One B-rep face of a CAD part: STEP entity #197.
In plain terms, the planar face has unit normal (1, 0, 0).
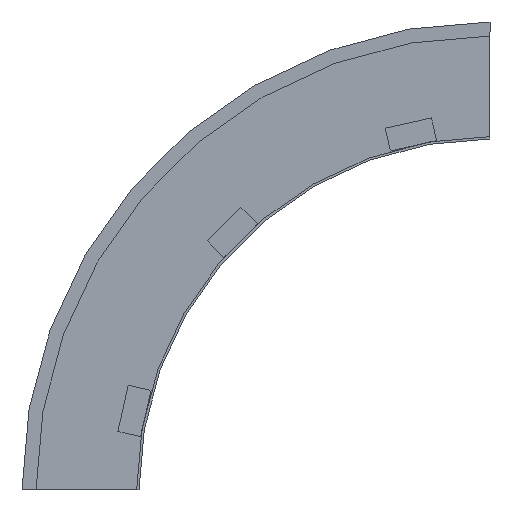
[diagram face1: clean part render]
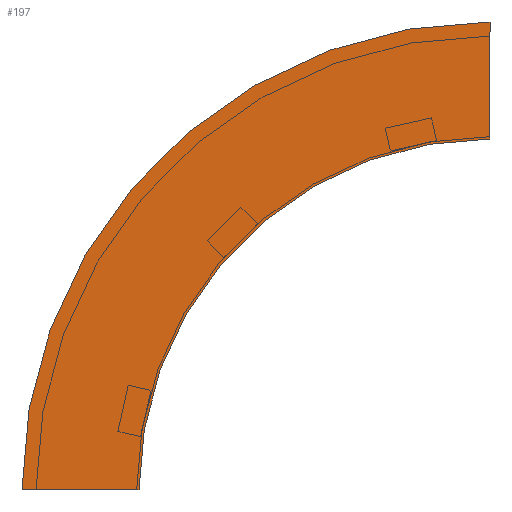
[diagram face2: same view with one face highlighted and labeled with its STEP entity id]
Its self-contained STEP definition (entity closure, numbers rounded to 3 decimals):
#60 = CIRCLE ( 'NONE', #221, 300. ) ;
#65 = DIRECTION ( 'NONE',  ( 0., 1., 0. ) ) ;
#71 = VECTOR ( 'NONE', #213, 1000. ) ;
#105 = CARTESIAN_POINT ( 'NONE',  ( 0., 0., 0. ) ) ;
#115 = ORIENTED_EDGE ( 'NONE', *, *, #181, .T. ) ;
#139 = EDGE_CURVE ( 'NONE', #254, #363, #551, .T. ) ;
#148 = CARTESIAN_POINT ( 'NONE',  ( 0., -300., 0. ) ) ;
#160 = CARTESIAN_POINT ( 'NONE',  ( 0., -300., 400. ) ) ;
#172 = EDGE_LOOP ( 'NONE', ( #115, #370, #451, #264 ) ) ;
#181 = EDGE_CURVE ( 'NONE', #363, #540, #483, .T. ) ;
#194 = DIRECTION ( 'NONE',  ( 0., 1., 0. ) ) ;
#197 = ADVANCED_FACE ( 'NONE', ( #467 ), #337, .T. ) ;
#213 = DIRECTION ( 'NONE',  ( 0., 0., 1. ) ) ;
#221 = AXIS2_PLACEMENT_3D ( 'NONE', #148, #541, #194 ) ;
#228 = CARTESIAN_POINT ( 'NONE',  ( 0., 100., 0. ) ) ;
#235 = VERTEX_POINT ( 'NONE', #439 ) ;
#243 = DIRECTION ( 'NONE',  ( 1., 0., 0. ) ) ;
#254 = VERTEX_POINT ( 'NONE', #105 ) ;
#264 = ORIENTED_EDGE ( 'NONE', *, *, #139, .T. ) ;
#309 = CARTESIAN_POINT ( 'NONE',  ( 0., -300., 300. ) ) ;
#337 = PLANE ( 'NONE',  #466 ) ;
#341 = CARTESIAN_POINT ( 'NONE',  ( 0., 0., 0. ) ) ;
#345 = AXIS2_PLACEMENT_3D ( 'NONE', #469, #387, #429 ) ;
#363 = VERTEX_POINT ( 'NONE', #228 ) ;
#370 = ORIENTED_EDGE ( 'NONE', *, *, #494, .F. ) ;
#387 = DIRECTION ( 'NONE',  ( 1., 0., 0. ) ) ;
#397 = DIRECTION ( 'NONE',  ( 0., 0., -1. ) ) ;
#429 = DIRECTION ( 'NONE',  ( 0., 1., 0. ) ) ;
#439 = CARTESIAN_POINT ( 'NONE',  ( 0., -300., 300. ) ) ;
#451 = ORIENTED_EDGE ( 'NONE', *, *, #574, .F. ) ;
#466 = AXIS2_PLACEMENT_3D ( 'NONE', #341, #243, #397 ) ;
#467 = FACE_OUTER_BOUND ( 'NONE', #172, .T. ) ;
#469 = CARTESIAN_POINT ( 'NONE',  ( 0., -300., 0. ) ) ;
#483 = CIRCLE ( 'NONE', #345, 400. ) ;
#494 = EDGE_CURVE ( 'NONE', #235, #540, #565, .T. ) ;
#515 = CARTESIAN_POINT ( 'NONE',  ( 0., 0., 0. ) ) ;
#538 = VECTOR ( 'NONE', #65, 1000. ) ;
#540 = VERTEX_POINT ( 'NONE', #160 ) ;
#541 = DIRECTION ( 'NONE',  ( 1., 0., 0. ) ) ;
#551 = LINE ( 'NONE', #515, #538 ) ;
#565 = LINE ( 'NONE', #309, #71 ) ;
#574 = EDGE_CURVE ( 'NONE', #254, #235, #60, .T. ) ;
